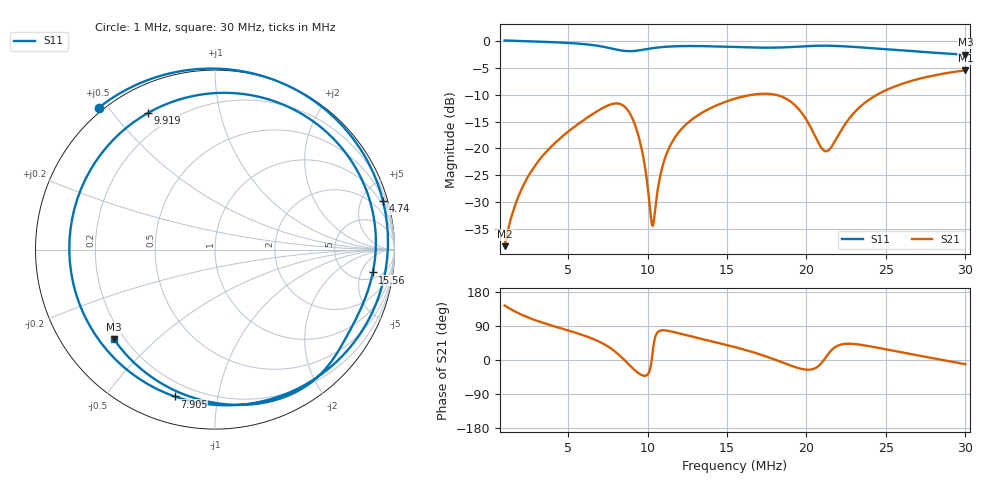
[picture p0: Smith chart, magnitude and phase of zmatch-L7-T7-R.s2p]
# HZ S RI R 50
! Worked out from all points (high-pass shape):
!   505 points, 1 MHz to 30 MHz, reference 50 ohm
!   highest |S21| = -5.40 dB at 30 MHz (marker M1); lowest = -38.3 dB at 1 MHz (marker M2)
!   |S21| within 3 dB of the highest: 25.56 MHz to end of sweep
!   lowest |S11| = -2.5 dB at 30 MHz (marker M3), VSWR 7.08, Z = 8.06 - j18.5 ohm
!   |S11| at or under -10 dB: nowhere
!   S12 and S22 are empty: the file has one direction only
!   S11 on the Smith chart (normalised r, x): 1 MHz: -0.01, +0.47; 4.74 MHz: 0.66, +7.00; 7.905 MHz: 0.13, -0.75; 9.919 MHz: 0.11, +0.62; 15.56 MHz: 7, -8; 30 MHz: 0.16, -0.37
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1000000  -0.6485 0.7901  -0.00985 0.00721  0 0  0 0
1748020  -0.2068 0.9912  -0.0188 0.0259  0 0  0 0
2553580  0.2457 0.9725  -0.0204 0.0534  0 0  0 0
3646840  0.7007 0.6994  -0.00809 0.0936  0 0  0 0
4740100  0.9358 0.2705  0.0208 0.1321  0 0  0 0
5833360  0.919 -0.2411  0.0698 0.1637  0 0  0 0
6869080  0.5662 -0.7135  0.1444 0.1724  0 0  0 0
7904800  -0.2249 -0.8184  0.2404 0.1063  0 0  0 0
8882980  -0.8089 -0.0674  0.2056 -0.0535  0 0  0 0
9343300  -0.7217 0.3925  0.1218 -0.0768  0 0  0 0
9918700  -0.3724 0.7619  0.0419 -0.0361  0 0  0 0
1.032148e7  -0.0936 0.8613  0.0175 0.00704  0 0  0 0
1.066672e7  0.1224 0.8706  0.0116 0.0424  0 0  0 0
1.13572e7  0.4544 0.7723  0.0237 0.0987  0 0  0 0
1.256554e7  0.7672 0.4822  0.0762 0.1579  0 0  0 0
1.550008e7  0.881 -0.1183  0.242 0.1634  0 0  0 0
1.555762e7  0.8792 -0.1274  0.2452 0.1615  0 0  0 0
1.843462e7  0.7344 -0.4826  0.3039 -0.0299  0 0  0 0
2.033344e7  0.589 -0.6928  0.1366 -0.063  0 0  0 0
2.131162e7  0.4683 -0.784  0.0924 0.0207  0 0  0 0
2.51668e7  -0.0699 -0.8397  0.3206 0.1627  0 0  0 0
3.000016e7  -0.5632 -0.499  0.5268 -0.104  0 0  0 0
